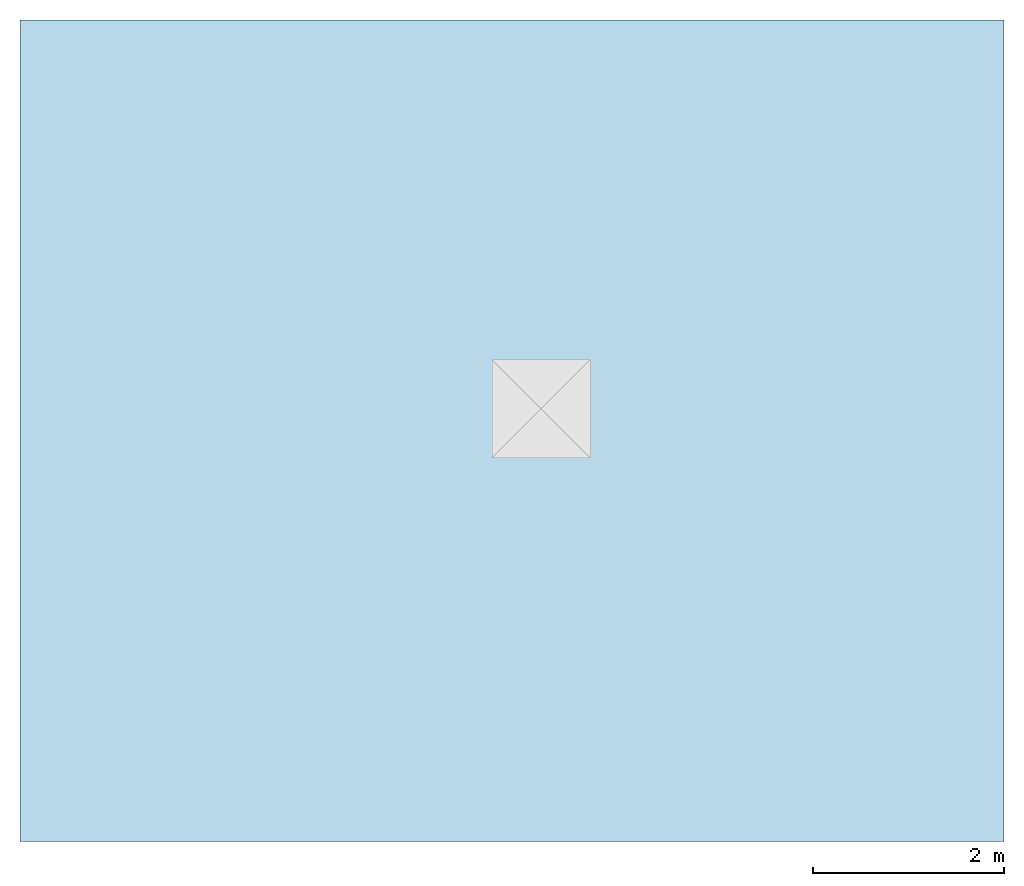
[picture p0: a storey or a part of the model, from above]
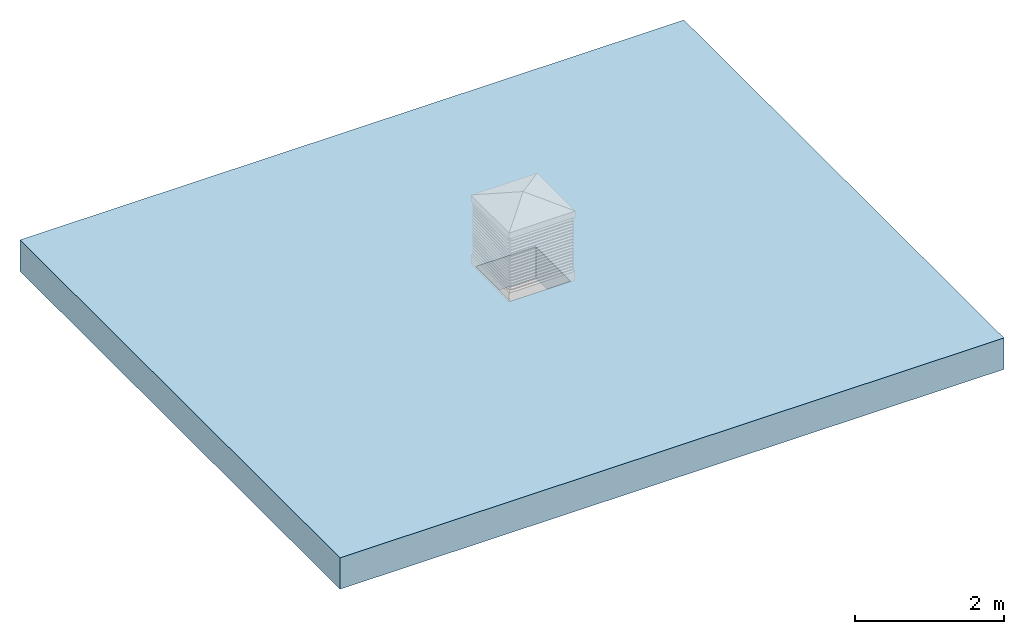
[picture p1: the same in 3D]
Properties of the parts of a building model (IFC2X3)

# File
Description: ViewDefinition [CoordinationView_V2.0], RevitIdentifiers [VersionGUID: 55575a9d-8d26-4a32-a262-e1bdbb343a08, NumberOfSaves: 0], CoordinateReference [CoordinateBase: Shared Coordinates, ProjectSite: Default Site]
File name: WBR_Passivent_NaturalVentilationSystems_AirstractRoofTerminal_1025x1025mm_June 2021.ifc
Time: 2025-06-25T11:01:24
Written by: ODA IFC SDK 22.8
Made in: 22.1.80.32 - IFC 22.7.0.0 - Default UI

# IfcProject, Project Number
LongName: Project Name; Phase: Project Status

# IfcSite, Default
RefLatitude: 51, 30, 23, 112487; RefLongitude: 0, -7, -37, -956022; RefElevation: 0 mm

# IfcBuilding
Pset_BuildingCommon - NumberOfStoreys: 1

# IfcBuildingStorey: Level:Circle Head - Project Datum (2)
Pset_AirSideSystemInformation - sets with these values: 2
Name | LongName = Name | Elevation (mm)
Level 0 | Level 0 | 0
Level 1 | Level 1 | 4000

# IfcFlowTerminal: WBR_Passivent_NaturalVentilationSystems_AirstractRoofTerminal_1025x1025mm_June 2021:AirstractRoofTerminal_1025x1025mm, WBR_Passivent_NaturalVentilationSystems_AirstractRoofTerminal_1025x1025mm_June 2021:AirstractRoofTerminal_1025x1025mm:313739
In: Level 0
Type - PredefinedType: GRILLE; Material: WBR_Passivent_Aluminum
Type - Pset_AirTerminalTypeCommon - Shape: OTHER
Type - Pset_ElementShading - Color: RAL 9016
Type - Pset_ManufacturerTypeInformation - ModelReference: Airstract Roof Terminal 1025x1025mm; Manufacturer: Passivent
Type - Pset_ProductRequirements - Name: NaturalVentilationSystems_AirstractRoofTerminal_Passivent
Pset_DistributionFlowElementCommon - Reference: AirstractRoofTerminal_1025x1025mm; sets with these values: 2
Pset_ManufacturerOccurrence - BarCode: n/a; SerialNumber: n/a

# IfcOpeningElement: Opening, Basic Roof:Roof_Pitched-50SS-220Ins-20MPan-225Purl:309835:1
In: Level 0
Pset_OpeningElementCommon - Reference: Roof_Pitched-50SS-220Ins-20MPan-225Purl; sets with these values: 2

# IfcRoof: Basic Roof:Roof_Pitched-50SS-220Ins-20MPan-225Purl, Basic Roof:Roof_Pitched-50SS-220Ins-20MPan-225Purl:309835
In: Level 0
Material: Roofing, Standing Seam 50 mm, Rigid insulation 220 mm, Metal Panel 20 mm, Steel Purlins 225 mm
Pset_QuantityTakeOff - Reference: Roof_Pitched-50SS-220Ins-20MPan-225Purl
Pset_RoofCommon - Reference: Roof_Pitched-50SS-220Ins-20MPan-225Purl; IsExternal: yes; ProjectedArea: 88.58 m2; TotalArea: 87.7076 m2

# IfcSlab: Basic Roof:Roof_Pitched-50SS-220Ins-20MPan-225Purl, Basic Roof:Roof_Pitched-50SS-220Ins-20MPan-225Purl:309835:1
In: Level 0
Type - PredefinedType: ROOF
Type - Pset_SlabCommon - IsExternal: yes; ThermalTransmittance: 0.158928 kg/K/s3
Pset_QuantityTakeOff - Reference: Roof_Pitched-50SS-220Ins-20MPan-225Purl; sets with these values: 2
Pset_SlabCommon - Reference: Roof_Pitched-50SS-220Ins-20MPan-225Purl; PitchAngle: 0 deg
